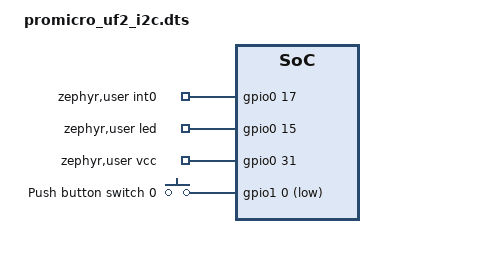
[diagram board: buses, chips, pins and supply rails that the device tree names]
// Copyright (c) 2024 Nordic Semiconductor ASA
// SPDX-License-Identifier: Apache-2.0

/dts-v1/;
#include "promicro_uf2.dts"

/delete-node/ &spi3;

&pinctrl {
	i2c0_default: i2c0_default {
		group1 {
			psels = <NRF_PSEL(TWIM_SDA, 0, 6)>, <NRF_PSEL(TWIM_SCL, 0, 8)>;
			bias-disable;
		};
	};

	i2c0_sleep: i2c0_sleep {
		group1 {
			psels = <NRF_PSEL(TWIM_SDA, 0, 6)>, <NRF_PSEL(TWIM_SCL, 0, 8)>;
			bias-disable;
			low-power-enable;
		};
	};
};

/ {
	zephyr,user {
		int0-gpios = <&gpio0 17 0>;
		led-gpios = <&gpio0 15 GPIO_OPEN_SOURCE>;
		vcc-gpios = <&gpio0 31 GPIO_ACTIVE_HIGH>;
	};

	buttons {
		compatible = "gpio-keys";
		button0: button_0 {
			gpios = <&gpio1 0 (GPIO_PULL_UP | GPIO_ACTIVE_LOW)>;
			label = "Push button switch 0";
		};
	};

	aliases {
		sw0 = &button0;
	};
};
	};
};
